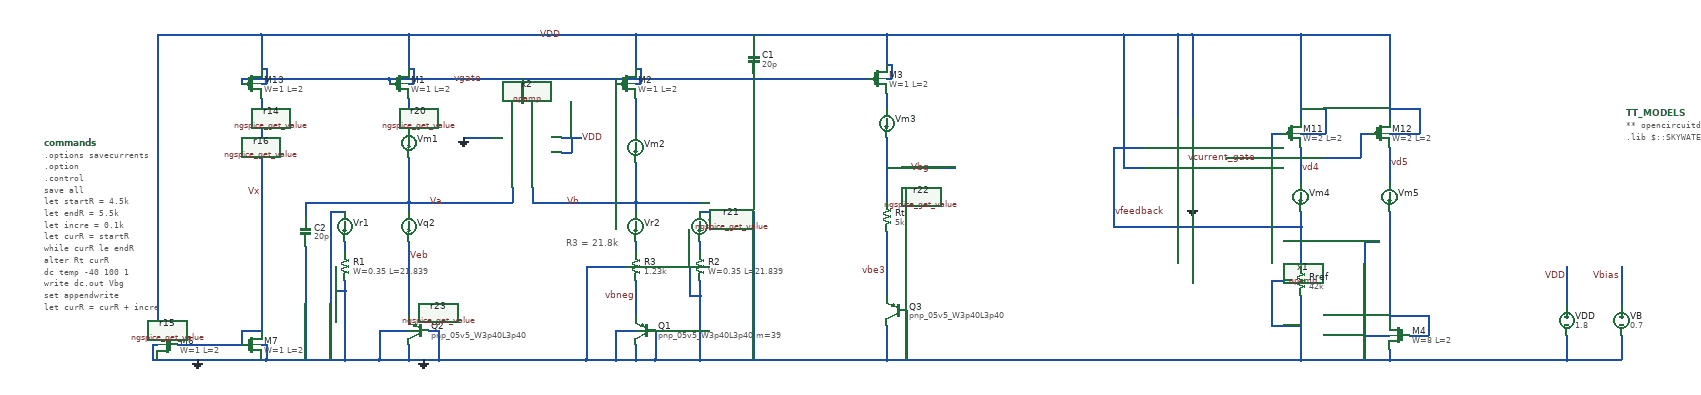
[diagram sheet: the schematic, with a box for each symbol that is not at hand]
v {xschem version=3.0.0 file_version=1.2 }
G {}
K {}
V {}
S {}
E {}
T {R3 = 21.8k} -650 -260 0 0 0.4 0.4 {}
N 1090 -10 1380 -10 {
lab=GND}
N 1380 -60 1380 -10 {
lab=GND}
N 1380 -200 1380 -120 {
lab=VDD}
N 1490 -60 1490 -10 {
lab=GND}
N 1490 -200 1490 -120 {
lab=Vbias}
N 1380 -10 1490 -10 {
lab=GND}
N -510 -330 -380 -330 { lab=Vb}
N -970 -40 -970 -10 { lab=GND}
N -1030 -70 -970 -70 { lab=GND}
N -1030 -70 -1030 -10 { lab=GND}
N -970 -670 -750 -670 { lab=VDD}
N -510 -670 -310 -670 { lab=VDD}
N -510 -330 -510 -310 { lab=Vb}
N -510 -410 -510 -330 { lab=Vb}
N 0 -460 0 -330 { lab=Vbg}
N -510 -250 -510 -230 { lab=#net1}
N -380 -250 -380 -230 { lab=#net2}
N -1100 -250 -1100 -230 { lab=#net3}
N -510 -540 -510 -470 { lab=#net4}
N -510 -170 -510 -100 { lab=vbneg}
N -1100 -150 -1100 -10 { lab=GND}
N -380 -140 -380 -10 { lab=GND}
N -470 -70 -470 -10 { lab=GND}
N -510 -40 -510 -10 { lab=GND}
N -550 -70 -510 -70 { lab=GND}
N -550 -70 -550 -10 { lab=GND}
N -930 -70 -910 -70 { lab=GND}
N -910 -70 -910 -10 { lab=GND}
N -1120 -200 -1120 -150 { lab=GND}
N -1120 -150 -1100 -150 { lab=GND}
N -400 -200 -400 -140 { lab=GND}
N -400 -140 -380 -140 { lab=GND}
N -610 -200 -530 -200 { lab=GND}
N -610 -200 -610 -10 { lab=GND}
N -970 -250 -970 -100 { lab=Veb}
N -620 -330 -510 -330 { lab=Vb}
N -1490 -40 -1480 -40 { lab=GND}
N -1490 -40 -1490 -10 { lab=GND}
N -1440 -40 -1310 -40 { lab=Vx}
N -1270 -40 -1260 -40 { lab=GND}
N -1310 -70 -1310 -40 { lab=Vx}
N -1310 -70 -1270 -70 { lab=Vx}
N -1260 -40 -1260 -10 { lab=GND}
N -120 -670 0 -670 { lab=VDD}
N -510 -670 -510 -600 { lab=VDD}
N 0 -580 10 -580 { lab=VDD}
N 10 -610 10 -580 { lab=VDD}
N 0 -610 10 -610 { lab=VDD}
N -120 -10 0 -10 { lab=GND}
N -970 -330 -970 -310 { lab=Va}
N -550 -580 -550 -570 { lab=vgate}
N -1010 -580 -1010 -570 { lab=vgate}
N -970 -540 -970 -480 { lab=#net5}
N -1270 -570 -1260 -570 { lab=VDD}
N -1260 -600 -1260 -570 { lab=VDD}
N -1270 -600 -1260 -600 { lab=VDD}
N -970 -570 -960 -570 { lab=VDD}
N -960 -600 -960 -570 { lab=VDD}
N -970 -600 -960 -600 { lab=VDD}
N -970 -670 -970 -600 { lab=VDD}
N -510 -570 -500 -570 { lab=VDD}
N -500 -600 -500 -570 { lab=VDD}
N -510 -600 -500 -600 { lab=VDD}
N -1480 -460 -1480 -70 { lab=VDD}
N -1230 -670 -970 -670 { lab=VDD}
N -70 -580 -40 -580 { lab=vgate}
N -1310 -580 -1310 -570 { lab=vgate}
N -1270 -670 -1270 -600 { lab=VDD}
N -1270 -350 -1270 -70 { lab=Vx}
N -970 -330 -900 -330 { lab=Va}
N -1100 -330 -970 -330 { lab=Va}
N 0 -670 0 -610 { lab=VDD}
N 0 -550 0 -520 { lab=#net6}
N -1030 -10 -970 -10 { lab=GND}
N -1100 -10 -1030 -10 { lab=GND}
N -1220 -10 -1100 -10 { lab=GND}
N -470 -10 -380 -10 { lab=GND}
N -510 -10 -470 -10 { lab=GND}
N -550 -10 -510 -10 { lab=GND}
N -610 -10 -550 -10 { lab=GND}
N -970 -10 -910 -10 { lab=GND}
N -1100 -170 -1100 -150 { lab=GND}
N -380 -170 -380 -140 { lab=GND}
N -910 -10 -850 -10 { lab=GND}
N 0 -270 0 -250 { lab=vbe3}
N -1490 -10 -1260 -10 { lab=GND}
N -310 -670 -120 -670 { lab=VDD}
N -1270 -540 -1270 -350 { lab=Vx}
N -1010 -580 -790 -580 { lab=vgate}
N -790 -580 -310 -580 { lab=vgate}
N -970 -420 -970 -330 { lab=Va}
N -1270 -670 -1230 -670 { lab=VDD}
N -1260 -10 -1220 -10 { lab=GND}
N -1170 -580 -1010 -580 { lab=vgate}
N -1310 -580 -1170 -580 { lab=vgate}
N -1180 -330 -1180 -300 { lab=Va}
N -270 -670 -270 -650 { lab=VDD}
N -270 -590 -270 -580 { lab=vgate}
N -1180 -240 -1180 -10 { lab=GND}
N -1180 -330 -1100 -330 { lab=Va}
N 0 -670 300 -670 {
lab=VDD}
N 590 -670 620 -670 {
lab=VDD}
N 590 -670 590 -500 {
lab=VDD}
N 620 -670 620 -500 {
lab=VDD}
N 460 -440 520 -440 {
lab=vfeedback}
N 690 -420 740 -420 {
lab=vcurrent_gate}
N 740 -420 800 -420 {
lab=vcurrent_gate}
N 620 -670 840 -670 {
lab=VDD}
N 460 -440 460 -280 {
lab=vfeedback}
N 460 -280 840 -280 {
lab=vfeedback}
N 620 -360 620 -320 {
lab=GND}
N 840 -280 840 -200 {
lab=vfeedback}
N 840 -140 840 -10 {
lab=GND}
N 0 -10 550 -10 {
lab=GND}
N 840 -390 840 -370 {
lab=vd4}
N 840 -310 840 -280 {
lab=vfeedback}
N 780 -170 820 -170 {
lab=GND}
N 780 -170 780 -80 {
lab=GND}
N 780 -80 840 -80 {
lab=GND}
N 840 -440 840 -390 {
lab=vd4}
N 780 -470 780 -420 {
lab=vcurrent_gate}
N 780 -470 800 -470 {
lab=vcurrent_gate}
N 840 -670 840 -500 {
lab=VDD}
N 1020 -390 1020 -370 {
lab=vd5}
N 1020 -440 1020 -390 {
lab=vd5}
N 960 -470 960 -420 {
lab=vcurrent_gate}
N 960 -470 980 -470 {
lab=vcurrent_gate}
N 800 -420 960 -420 {
lab=vcurrent_gate}
N 1020 -670 1020 -500 {
lab=VDD}
N 840 -670 1020 -670 {
lab=VDD}
N 1020 -30 1020 -10 {
lab=GND}
N 840 -10 1020 -10 {
lab=GND}
N 1020 -120 1020 -90 {
lab=#net7}
N 970 -150 970 -10 {
lab=GND}
N 970 -60 1020 -60 {
lab=GND}
N 840 -470 890 -470 {
lab=VDD}
N 890 -520 890 -470 {
lab=VDD}
N 840 -520 890 -520 {
lab=VDD}
N 1020 -470 1080 -470 {
lab=VDD}
N 1080 -520 1080 -470 {
lab=VDD}
N 1020 -520 1080 -520 {
lab=VDD}
N 1020 -310 1020 -280 {
lab=#net7}
N 1060 -60 1100 -60 {
lab=#net7}
N 970 -250 1000 -250 {
lab=GND}
N 970 -250 970 -150 {
lab=GND}
N -720 -330 -620 -330 {
lab=Vb}
N -720 -360 -720 -330 {
lab=Vb}
N -900 -330 -760 -330 {
lab=Va}
N -760 -360 -760 -330 {
lab=Va}
N -740 -580 -740 -530 {
lab=vgate}
N -750 -670 -510 -670 {
lab=VDD}
N -310 -580 -70 -580 {
lab=vgate}
N -850 -10 -610 -10 {
lab=GND}
N -380 -10 -120 -10 {
lab=GND}
N -860 -460 -800 -460 {
lab=GND}
N -660 -460 -620 -460 {
lab=VDD}
N -660 -430 -640 -430 {
lab=VDD}
N -640 -460 -640 -430 {
lab=VDD}
N 1100 -100 1100 -60 {
lab=#net7}
N 1020 -100 1100 -100 {
lab=#net7}
N 1020 -280 1020 -220 {
lab=#net7}
N 1020 -220 1020 -120 {
lab=#net7}
N 480 -400 520 -400 {
lab=VDD}
N 480 -670 480 -400 {
lab=VDD}
N 0 -250 0 -140 {
lab=vbe3}
N 0 -80 0 -10 {
lab=GND}
N 40 -110 40 -10 {
lab=GND}
N 0 -400 140 -400 {
lab=Vbg}
N -1480 -670 -1480 -460 {
lab=VDD}
N -1480 -670 -1270 -670 {
lab=VDD}
N 480 -670 590 -670 {
lab=VDD}
N 300 -670 480 -670 {
lab=VDD}
N 550 -10 840 -10 {
lab=GND}
N -1130 -310 -1100 -310 {
lab=GND}
N -1130 -310 -1130 -10 {
lab=GND}
N -380 -310 -270 -310 {
lab=GND}
N -270 -310 -270 -10 {
lab=GND}
N 1020 -10 1090 -10 {
lab=GND}
C {vsource.sym} 1380 -90 0 0 {name=VDD value=1.8}
C {lab_wire.sym} 1380 -180 0 0 {name=l7 sig_type=std_logic lab=VDD}
C {devices/code.sym} 1500 -510 0 0 {name=TT_MODELS
only_toplevel=true
format="tcleval( @value )"
value="
** opencircuitdesign pdks install
.lib $::SKYWATER_MODELS/sky130.lib.spice tt

"
spice_ignore=false}
C {vsource.sym} 1490 -90 0 0 {name=VB value=0.7}
C {lab_wire.sym} 1490 -180 0 0 {name=l9 sig_type=std_logic lab=Vbias}
C {sky130_fd_pr/pnp_05v5.sym} -950 -70 0 1 {name=Q2
model=pnp_05v5_W3p40L3p40
spiceprefix=X
}
C {devices/gnd.sym} -940 -10 0 0 {name=l1 lab=GND}
C {devices/lab_pin.sym} -900 -330 3 0 {name=l5 lab=Va}
C {devices/lab_pin.sym} -620 -330 3 0 {name=l6 lab=Vb}
C {devices/ammeter.sym} -380 -280 0 0 {name=Vr4 current=5.7238e-06}
C {devices/ammeter.sym} -510 -280 0 0 {name=Vr2 current=4.3334e-06}
C {devices/ammeter.sym} -970 -450 0 0 {name=Vm1 current=1.0057e-05}
C {devices/ammeter.sym} -510 -440 0 0 {name=Vm2 current=1.0057e-05}
C {devices/ammeter.sym} 0 -490 0 0 {name=Vm3 current=1.0239e-05}
C {devices/ammeter.sym} -1100 -280 0 0 {name=Vr1 current=5.7228e-06}
C {devices/ammeter.sym} -970 -280 0 0 {name=Vq2 current=4.3346e-06}
C {sky130_fd_pr/pnp_05v5.sym} -490 -70 0 1 {name=Q1
model="pnp_05v5_W3p40L3p40 m=39"
spiceprefix=X
}
C {devices/lab_pin.sym} -510 -140 0 0 {name=l4 lab=vbneg}
C {devices/lab_pin.sym} -970 -220 2 0 {name=l10 lab=Veb}
C {devices/lab_wire.sym} -820 -580 0 0 {name=l11 lab=vgate}
C {sky130_fd_pr/nfet_01v8_lvt.sym} -1460 -40 0 1 {name=M6
L=2
W=1
nf=1
mult=3.65
ad="'int((nf+1)/2) * W/nf * 0.29'" 
pd="'2*int((nf+1)/2) * (W/nf + 0.29)'"
as="'int((nf+2)/2) * W/nf * 0.29'" 
ps="'2*int((nf+2)/2) * (W/nf + 0.29)'"
nrd="'0.29 / W'" nrs="'0.29 / W'"
sa=0 sb=0 sd=0
model=nfet_01v8_lvt
spiceprefix=X
}
C {devices/lab_pin.sym} -1270 -350 1 0 {name=l12 lab=Vx}
C {sky130_fd_pr/nfet_01v8_lvt.sym} -1290 -40 0 0 {name=M7
L=2
W=1
nf=1
mult=3.65
ad="'int((nf+1)/2) * W/nf * 0.29'" 
pd="'2*int((nf+1)/2) * (W/nf + 0.29)'"
as="'int((nf+2)/2) * W/nf * 0.29'" 
ps="'2*int((nf+2)/2) * (W/nf + 0.29)'"
nrd="'0.29 / W'" nrs="'0.29 / W'"
sa=0 sb=0 sd=0
model=nfet_01v8_lvt
spiceprefix=X
}
C {sky130_fd_pr/pfet_01v8_lvt.sym} -1290 -570 0 0 {name=M13
L=2
W=1
nf=1
mult=77.32
ad="'int((nf+1)/2) * W/nf * 0.29'" 
pd="'2*int((nf+1)/2) * (W/nf + 0.29)'"
as="'int((nf+2)/2) * W/nf * 0.29'" 
ps="'2*int((nf+2)/2) * (W/nf + 0.29)'"
nrd="'0.29 / W'" nrs="'0.29 / W'"
sa=0 sb=0 sd=0
model=pfet_01v8_lvt
spiceprefix=X
}
C {sky130_fd_pr/pfet_01v8_lvt.sym} -990 -570 0 0 {name=M1
L=2
W=1
nf=1
mult=200
ad="'int((nf+1)/2) * W/nf * 0.29'" 
pd="'2*int((nf+1)/2) * (W/nf + 0.29)'"
as="'int((nf+2)/2) * W/nf * 0.29'" 
ps="'2*int((nf+2)/2) * (W/nf + 0.29)'"
nrd="'0.29 / W'" nrs="'0.29 / W'"
sa=0 sb=0 sd=0
model=pfet_01v8_lvt
spiceprefix=X
}
C {sky130_fd_pr/pfet_01v8_lvt.sym} -530 -570 0 0 {name=M2
L=2
W=1
nf=1
mult=200
ad="'int((nf+1)/2) * W/nf * 0.29'" 
pd="'2*int((nf+1)/2) * (W/nf + 0.29)'"
as="'int((nf+2)/2) * W/nf * 0.29'" 
ps="'2*int((nf+2)/2) * (W/nf + 0.29)'"
nrd="'0.29 / W'" nrs="'0.29 / W'"
sa=0 sb=0 sd=0
model=pfet_01v8_lvt
spiceprefix=X
}
C {sky130_fd_pr/pfet_01v8_lvt.sym} -20 -580 0 0 {name=M3
L=2
W=1
nf=1
mult=200
ad="'int((nf+1)/2) * W/nf * 0.29'" 
pd="'2*int((nf+1)/2) * (W/nf + 0.29)'"
as="'int((nf+2)/2) * W/nf * 0.29'" 
ps="'2*int((nf+2)/2) * (W/nf + 0.29)'"
nrd="'0.29 / W'" nrs="'0.29 / W'"
sa=0 sb=0 sd=0
model=pfet_01v8_lvt
spiceprefix=X
}
C {sky130_fd_pr/res_xhigh_po_0p35.sym} -1100 -200 0 0 {name=R1
W=0.35
L=21.839
model=res_xhigh_po_0p35
spiceprefix=X
mult=1}
C {sky130_fd_pr/res_xhigh_po_0p35.sym} -380 -200 0 0 {name=R2
W=0.35
L=21.839
model=res_xhigh_po_0p35
spiceprefix=X
mult=1}
C {devices/ngspice_probe.sym} -970 -330 0 0 {name=r1}
C {devices/ngspice_probe.sym} -510 -330 0 0 {name=r2}
C {devices/ngspice_probe.sym} -1270 -320 0 0 {name=r3}
C {devices/ngspice_probe.sym} -820 -580 0 0 {name=r5}
C {devices/ngspice_probe.sym} -510 -140 0 0 {name=r9}
C {devices/ngspice_get_value.sym} -1270 -440 0 0 {name=r16 node=i(@m.xm13.msky130_fd_pr__pfet_01v8_lvt[id])
descr="I="}
C {devices/ngspice_get_value.sym} -1250 -500 0 0 {name=r14 node=@m.xm13.msky130_fd_pr__pfet_01v8_lvt[gm]
descr="gm="}
C {devices/ngspice_get_value.sym} -950 -500 0 0 {name=r20 node=@m.xm1.msky130_fd_pr__pfet_01v8_lvt[gm]
descr="gm="}
C {devices/ngspice_get_value.sym} -540 -500 0 1 {name=r21 node=@m.xm2.msky130_fd_pr__pfet_01v8_lvt[gm]
descr="gm="}
C {devices/ngspice_get_value.sym} 10 -530 0 0 {name=r22 node=@m.xm3.msky130_fd_pr__pfet_01v8_lvt[gm]
descr="gm="}
C {devices/ngspice_get_value.sym} -1460 -70 0 0 {name=r15 node=@m.xm6.msky130_fd_pr__nfet_01v8_lvt[gm]
descr="gm="}
C {devices/ngspice_get_value.sym} -1290 -70 0 1 {name=r23 node=@m.xm7.msky130_fd_pr__nfet_01v8_lvt[gm]
descr="gm="}
C {devices/gnd.sym} -1400 -10 0 0 {name=l17 lab=GND}
C {devices/capa.sym} -270 -620 0 0 {name=C1
m=1
value=20p
footprint=1206
device="ceramic capacitor"}
C {devices/capa.sym} -1180 -270 0 0 {name=C2
m=1
value=20p
footprint=1206
device="ceramic capacitor"}
C {sky130_fd_pr/pfet_01v8_lvt.sym} 820 -470 0 0 {name=M11
L=2
W=2
nf=1
mult=40
ad="'int((nf+1)/2) * W/nf * 0.29'" 
pd="'2*int((nf+1)/2) * (W/nf + 0.29)'"
as="'int((nf+2)/2) * W/nf * 0.29'" 
ps="'2*int((nf+2)/2) * (W/nf + 0.29)'"
nrd="'0.29 / W'" nrs="'0.29 / W'"
sa=0 sb=0 sd=0
model=pfet_01v8_lvt
spiceprefix=X
}
C {devices/gnd.sym} 620 -320 0 0 {name=l13 lab=GND}
C {devices/ammeter.sym} 840 -340 0 0 {name=Vm4 current=1.0239e-05}
C {design/opamp/opamp.sym} 620 -420 0 0 {name=x1}
C {devices/lab_pin.sym} 460 -310 0 1 {name=l20 lab=vfeedback}
C {devices/lab_pin.sym} 750 -420 1 0 {name=l21 lab=vcurrent_gate}
C {sky130_fd_pr/pfet_01v8_lvt.sym} 1000 -470 0 0 {name=M12
L=2
W=2
nf=1
mult=40
ad="'int((nf+1)/2) * W/nf * 0.29'" 
pd="'2*int((nf+1)/2) * (W/nf + 0.29)'"
as="'int((nf+2)/2) * W/nf * 0.29'" 
ps="'2*int((nf+2)/2) * (W/nf + 0.29)'"
nrd="'0.29 / W'" nrs="'0.29 / W'"
sa=0 sb=0 sd=0
model=pfet_01v8_lvt
spiceprefix=X
}
C {devices/ammeter.sym} 1020 -340 0 0 {name=Vm5 current=1.0239e-05}
C {sky130_fd_pr/nfet_01v8_lvt.sym} 1040 -60 0 1 {name=M4
L=2
W=8
nf=1
mult=10
ad="'int((nf+1)/2) * W/nf * 0.29'" 
pd="'2*int((nf+1)/2) * (W/nf + 0.29)'"
as="'int((nf+2)/2) * W/nf * 0.29'" 
ps="'2*int((nf+2)/2) * (W/nf + 0.29)'"
nrd="'0.29 / W'" nrs="'0.29 / W'"
sa=0 sb=0 sd=0
model=nfet_01v8_lvt
spiceprefix=X
}
C {res.sym} 840 -170 0 0 {name=Rref
value=42k
footprint=1206
device=resistor
m=1}
C {design/opamp/opamp.sym} -740 -460 1 1 {name=x2}
C {devices/gnd.sym} -860 -460 0 0 {name=l3 lab=GND}
C {devices/lab_wire.sym} -620 -460 0 1 {name=l14 lab=VDD}
C {devices/lab_pin.sym} 1020 -410 0 1 {name=l24 lab=vd5}
C {devices/lab_pin.sym} 840 -400 0 1 {name=l25 lab=vd4}
C {res.sym} 0 -300 0 0 {name=Rt
value=5k
footprint=1206
device=resistor
m=1}
C {devices/lab_pin.sym} 0 -190 0 0 {name=l15 lab=vbe3}
C {sky130_fd_pr/pnp_05v5.sym} 20 -110 0 1 {name=Q3
model=pnp_05v5_W3p40L3p40
*model="pnp_05v5_W3p40L3p40 m=4"
spiceprefix=X
}
C {lab_wire.sym} 90 -400 0 0 {name=l8 sig_type=std_logic lab=Vbg}
C {lab_wire.sym} -660 -670 0 0 {name=l16 sig_type=std_logic lab=VDD}
C {res.sym} -510 -200 0 0 {name=R3
value=1.23k
footprint=1206
device=resistor
m=1}
C {code.sym} -1710 -450 0 0 {name=commands only_toplevel=false value="
.options savecurrents


.option
.control
save all
let startR = 4.5k
let endR = 5.5k
let incre = 0.1k
let curR = startR
while curR le endR
alter Rt curR
dc temp -40 100 1
write dc.out Vbg
set appendwrite
let curR = curR + incre
end
run

plot dc1.Vbg dc2.Vbg dc3.Vbg dc4.Vbg dc5.Vbg dc6.Vbg dc7.Vbg dc8.Vbg dc9.Vbg dc10.Vbg


.endc

*** plot voltage coefficient
*Vdd VDD GND 3.3
*V_en en GND 3.3
*.dc Vdd 2 4 0.1
*.control
*run
*plot deriv(V(Vbgp))
*.endc

*** plot temperature coefficient
*Vdd VDD GND 3.3
*V_en en GND 3.3
*.dc temp -40 140 1
*.control
*run
*plot deriv(V(Vbgp))/1.202344
*.endc



*** enable pin
*Vdd VDD GND 3.3
*V_en en GND PULSE(0 3.3 0 200us 200us 600us 2000us 0)
*.tran 1u 2000us
*.control
*run
*plot V(en)
*plot -I(VDD)
*.endc
"}
